VERSION 5.7 ;
  NOWIREEXTENSIONATPIN ON ;
  DIVIDERCHAR "/" ;
  BUSBITCHARS "[]" ;
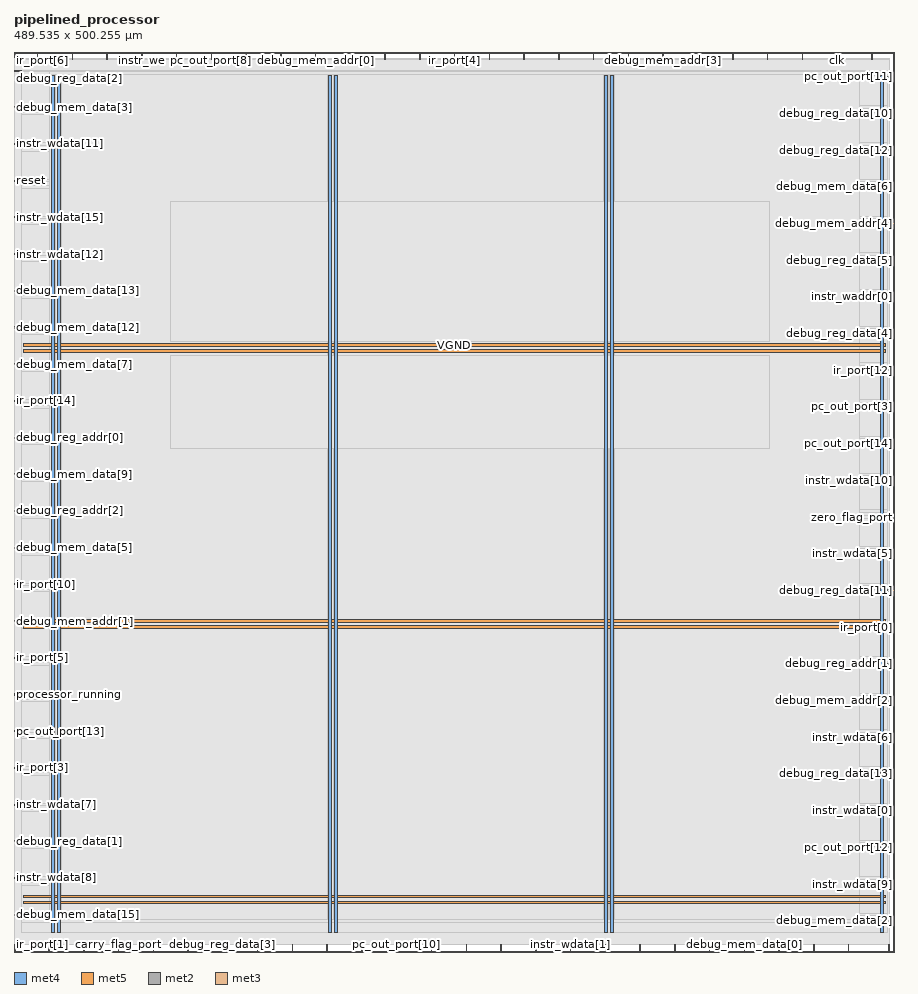
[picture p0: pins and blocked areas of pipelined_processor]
MACRO pipelined_processor
  CLASS BLOCK ;
  FOREIGN pipelined_processor ;
  ORIGIN 0.000 0.000 ;
  SIZE 489.535 BY 500.255 ;
  PIN VGND
    DIRECTION INOUT ;
    USE GROUND ;
    PORT
      LAYER met4 ;
        RECT 24.340 10.640 25.940 487.120 ;
    END
    PORT
      LAYER met4 ;
        RECT 177.940 10.640 179.540 487.120 ;
    END
    PORT
      LAYER met4 ;
        RECT 331.540 10.640 333.140 487.120 ;
    END
    PORT
      LAYER met5 ;
        RECT 5.280 30.030 484.160 31.630 ;
    END
    PORT
      LAYER met5 ;
        RECT 5.280 183.210 484.160 184.810 ;
    END
    PORT
      LAYER met5 ;
        RECT 5.280 336.390 484.160 337.990 ;
    END
  END VGND
  PIN VPWR
    DIRECTION INOUT ;
    USE POWER ;
    PORT
      LAYER met4 ;
        RECT 21.040 10.640 22.640 487.120 ;
    END
    PORT
      LAYER met4 ;
        RECT 174.640 10.640 176.240 487.120 ;
    END
    PORT
      LAYER met4 ;
        RECT 328.240 10.640 329.840 487.120 ;
    END
    PORT
      LAYER met4 ;
        RECT 481.840 10.640 483.440 487.120 ;
    END
    PORT
      LAYER met5 ;
        RECT 5.280 26.730 484.160 28.330 ;
    END
    PORT
      LAYER met5 ;
        RECT 5.280 179.910 484.160 181.510 ;
    END
    PORT
      LAYER met5 ;
        RECT 5.280 333.090 484.160 334.690 ;
    END
  END VPWR
  PIN carry_flag_port
    DIRECTION OUTPUT TRISTATE ;
    USE SIGNAL ;
    ANTENNADIFFAREA 0.795200 ;
    PORT
      LAYER met2 ;
        RECT 58.050 0.000 58.330 4.000 ;
    END
  END carry_flag_port
  PIN clk
    DIRECTION INPUT ;
    USE SIGNAL ;
    ANTENNAGATEAREA 1.721400 ;
    ANTENNADIFFAREA 0.869400 ;
    PORT
      LAYER met2 ;
        RECT 457.330 496.255 457.610 500.255 ;
    END
  END clk
  PIN debug_mem_addr[0]
    DIRECTION INPUT ;
    USE SIGNAL ;
    ANTENNAGATEAREA 0.196500 ;
    PORT
      LAYER met2 ;
        RECT 167.530 496.255 167.810 500.255 ;
    END
  END debug_mem_addr[0]
  PIN debug_mem_addr[1]
    DIRECTION INPUT ;
    USE SIGNAL ;
    ANTENNAGATEAREA 0.247500 ;
    PORT
      LAYER met3 ;
        RECT 0.000 183.640 4.000 184.240 ;
    END
  END debug_mem_addr[1]
  PIN debug_mem_addr[2]
    DIRECTION INPUT ;
    USE SIGNAL ;
    ANTENNAGATEAREA 0.213000 ;
    PORT
      LAYER met3 ;
        RECT 485.535 139.440 489.535 140.040 ;
    END
  END debug_mem_addr[2]
  PIN debug_mem_addr[3]
    DIRECTION INPUT ;
    USE SIGNAL ;
    ANTENNAGATEAREA 0.213000 ;
    PORT
      LAYER met2 ;
        RECT 360.730 496.255 361.010 500.255 ;
    END
  END debug_mem_addr[3]
  PIN debug_mem_addr[4]
    DIRECTION INPUT ;
    USE SIGNAL ;
    ANTENNAGATEAREA 0.213000 ;
    PORT
      LAYER met3 ;
        RECT 485.535 404.640 489.535 405.240 ;
    END
  END debug_mem_addr[4]
  PIN debug_mem_addr[5]
    DIRECTION INPUT ;
    USE SIGNAL ;
    ANTENNAGATEAREA 0.213000 ;
    PORT
      LAYER met2 ;
        RECT 322.090 496.255 322.370 500.255 ;
    END
  END debug_mem_addr[5]
  PIN debug_mem_data[0]
    DIRECTION OUTPUT TRISTATE ;
    USE SIGNAL ;
    ANTENNADIFFAREA 0.795200 ;
    PORT
      LAYER met2 ;
        RECT 405.810 0.000 406.090 4.000 ;
    END
  END debug_mem_data[0]
  PIN debug_mem_data[10]
    DIRECTION OUTPUT TRISTATE ;
    USE SIGNAL ;
    ANTENNADIFFAREA 0.795200 ;
    PORT
      LAYER met2 ;
        RECT 186.850 496.255 187.130 500.255 ;
    END
  END debug_mem_data[10]
  PIN debug_mem_data[11]
    DIRECTION OUTPUT TRISTATE ;
    USE SIGNAL ;
    ANTENNADIFFAREA 0.795200 ;
    PORT
      LAYER met2 ;
        RECT 425.130 0.000 425.410 4.000 ;
    END
  END debug_mem_data[11]
  PIN debug_mem_data[12]
    DIRECTION OUTPUT TRISTATE ;
    USE SIGNAL ;
    ANTENNADIFFAREA 0.795200 ;
    PORT
      LAYER met3 ;
        RECT 0.000 346.840 4.000 347.440 ;
    END
  END debug_mem_data[12]
  PIN debug_mem_data[13]
    DIRECTION OUTPUT TRISTATE ;
    USE SIGNAL ;
    ANTENNADIFFAREA 0.795200 ;
    PORT
      LAYER met3 ;
        RECT 0.000 367.240 4.000 367.840 ;
    END
  END debug_mem_data[13]
  PIN debug_mem_data[14]
    DIRECTION OUTPUT TRISTATE ;
    USE SIGNAL ;
    ANTENNADIFFAREA 0.795200 ;
    PORT
      LAYER met2 ;
        RECT 347.850 0.000 348.130 4.000 ;
    END
  END debug_mem_data[14]
  PIN debug_mem_data[15]
    DIRECTION OUTPUT TRISTATE ;
    USE SIGNAL ;
    ANTENNADIFFAREA 0.795200 ;
    PORT
      LAYER met3 ;
        RECT 0.000 20.440 4.000 21.040 ;
    END
  END debug_mem_data[15]
  PIN debug_mem_data[1]
    DIRECTION OUTPUT TRISTATE ;
    USE SIGNAL ;
    ANTENNADIFFAREA 0.795200 ;
    PORT
      LAYER met2 ;
        RECT 148.210 496.255 148.490 500.255 ;
    END
  END debug_mem_data[1]
  PIN debug_mem_data[2]
    DIRECTION OUTPUT TRISTATE ;
    USE SIGNAL ;
    ANTENNADIFFAREA 0.445500 ;
    PORT
      LAYER met3 ;
        RECT 485.535 17.040 489.535 17.640 ;
    END
  END debug_mem_data[2]
  PIN debug_mem_data[3]
    DIRECTION OUTPUT TRISTATE ;
    USE SIGNAL ;
    ANTENNADIFFAREA 0.795200 ;
    PORT
      LAYER met3 ;
        RECT 0.000 469.240 4.000 469.840 ;
    END
  END debug_mem_data[3]
  PIN debug_mem_data[4]
    DIRECTION OUTPUT TRISTATE ;
    USE SIGNAL ;
    ANTENNADIFFAREA 0.795200 ;
    PORT
      LAYER met2 ;
        RECT 463.770 0.000 464.050 4.000 ;
    END
  END debug_mem_data[4]
  PIN debug_mem_data[5]
    DIRECTION OUTPUT TRISTATE ;
    USE SIGNAL ;
    ANTENNADIFFAREA 0.795200 ;
    PORT
      LAYER met3 ;
        RECT 0.000 224.440 4.000 225.040 ;
    END
  END debug_mem_data[5]
  PIN debug_mem_data[6]
    DIRECTION OUTPUT TRISTATE ;
    USE SIGNAL ;
    ANTENNADIFFAREA 0.445500 ;
    PORT
      LAYER met3 ;
        RECT 485.535 425.040 489.535 425.640 ;
    END
  END debug_mem_data[6]
  PIN debug_mem_data[7]
    DIRECTION OUTPUT TRISTATE ;
    USE SIGNAL ;
    ANTENNADIFFAREA 0.795200 ;
    PORT
      LAYER met3 ;
        RECT 0.000 326.440 4.000 327.040 ;
    END
  END debug_mem_data[7]
  PIN debug_mem_data[8]
    DIRECTION OUTPUT TRISTATE ;
    USE SIGNAL ;
    ANTENNADIFFAREA 0.795200 ;
    PORT
      LAYER met2 ;
        RECT 51.610 496.255 51.890 500.255 ;
    END
  END debug_mem_data[8]
  PIN debug_mem_data[9]
    DIRECTION OUTPUT TRISTATE ;
    USE SIGNAL ;
    ANTENNADIFFAREA 0.795200 ;
    PORT
      LAYER met3 ;
        RECT 0.000 265.240 4.000 265.840 ;
    END
  END debug_mem_data[9]
  PIN debug_reg_addr[0]
    DIRECTION INPUT ;
    USE SIGNAL ;
    ANTENNAGATEAREA 0.247500 ;
    PORT
      LAYER met3 ;
        RECT 0.000 285.640 4.000 286.240 ;
    END
  END debug_reg_addr[0]
  PIN debug_reg_addr[1]
    DIRECTION INPUT ;
    USE SIGNAL ;
    ANTENNAGATEAREA 0.159000 ;
    PORT
      LAYER met3 ;
        RECT 485.535 159.840 489.535 160.440 ;
    END
  END debug_reg_addr[1]
  PIN debug_reg_addr[2]
    DIRECTION INPUT ;
    USE SIGNAL ;
    ANTENNAGATEAREA 0.247500 ;
    PORT
      LAYER met3 ;
        RECT 0.000 244.840 4.000 245.440 ;
    END
  END debug_reg_addr[2]
  PIN debug_reg_data[0]
    DIRECTION OUTPUT TRISTATE ;
    USE SIGNAL ;
    ANTENNADIFFAREA 0.795200 ;
    PORT
      LAYER met2 ;
        RECT 193.290 0.000 193.570 4.000 ;
    END
  END debug_reg_data[0]
  PIN debug_reg_data[10]
    DIRECTION OUTPUT TRISTATE ;
    USE SIGNAL ;
    ANTENNADIFFAREA 0.445500 ;
    PORT
      LAYER met3 ;
        RECT 485.535 465.840 489.535 466.440 ;
    END
  END debug_reg_data[10]
  PIN debug_reg_data[11]
    DIRECTION OUTPUT TRISTATE ;
    USE SIGNAL ;
    ANTENNADIFFAREA 0.795200 ;
    PORT
      LAYER met3 ;
        RECT 485.535 200.640 489.535 201.240 ;
    END
  END debug_reg_data[11]
  PIN debug_reg_data[12]
    DIRECTION OUTPUT TRISTATE ;
    USE SIGNAL ;
    ANTENNADIFFAREA 0.445500 ;
    PORT
      LAYER met3 ;
        RECT 485.535 445.440 489.535 446.040 ;
    END
  END debug_reg_data[12]
  PIN debug_reg_data[13]
    DIRECTION OUTPUT TRISTATE ;
    USE SIGNAL ;
    ANTENNADIFFAREA 0.445500 ;
    PORT
      LAYER met3 ;
        RECT 485.535 98.640 489.535 99.240 ;
    END
  END debug_reg_data[13]
  PIN debug_reg_data[14]
    DIRECTION OUTPUT TRISTATE ;
    USE SIGNAL ;
    ANTENNADIFFAREA 0.795200 ;
    PORT
      LAYER met2 ;
        RECT 302.770 496.255 303.050 500.255 ;
    END
  END debug_reg_data[14]
  PIN debug_reg_data[15]
    DIRECTION OUTPUT TRISTATE ;
    USE SIGNAL ;
    ANTENNADIFFAREA 0.795200 ;
    PORT
      LAYER met2 ;
        RECT 225.490 496.255 225.770 500.255 ;
    END
  END debug_reg_data[15]
  PIN debug_reg_data[1]
    DIRECTION OUTPUT TRISTATE ;
    USE SIGNAL ;
    ANTENNADIFFAREA 0.795200 ;
    PORT
      LAYER met3 ;
        RECT 0.000 61.240 4.000 61.840 ;
    END
  END debug_reg_data[1]
  PIN debug_reg_data[2]
    DIRECTION OUTPUT TRISTATE ;
    USE SIGNAL ;
    ANTENNADIFFAREA 0.795200 ;
    PORT
      LAYER met3 ;
        RECT 0.000 489.640 4.000 490.240 ;
    END
  END debug_reg_data[2]
  PIN debug_reg_data[3]
    DIRECTION OUTPUT TRISTATE ;
    USE SIGNAL ;
    ANTENNADIFFAREA 0.795200 ;
    PORT
      LAYER met2 ;
        RECT 116.010 0.000 116.290 4.000 ;
    END
  END debug_reg_data[3]
  PIN debug_reg_data[4]
    DIRECTION OUTPUT TRISTATE ;
    USE SIGNAL ;
    ANTENNADIFFAREA 0.795200 ;
    PORT
      LAYER met3 ;
        RECT 485.535 343.440 489.535 344.040 ;
    END
  END debug_reg_data[4]
  PIN debug_reg_data[5]
    DIRECTION OUTPUT TRISTATE ;
    USE SIGNAL ;
    ANTENNADIFFAREA 0.795200 ;
    PORT
      LAYER met3 ;
        RECT 485.535 384.240 489.535 384.840 ;
    END
  END debug_reg_data[5]
  PIN debug_reg_data[6]
    DIRECTION OUTPUT TRISTATE ;
    USE SIGNAL ;
    ANTENNADIFFAREA 0.795200 ;
    PORT
      LAYER met2 ;
        RECT 206.170 496.255 206.450 500.255 ;
    END
  END debug_reg_data[6]
  PIN debug_reg_data[7]
    DIRECTION OUTPUT TRISTATE ;
    USE SIGNAL ;
    ANTENNADIFFAREA 0.795200 ;
    PORT
      LAYER met2 ;
        RECT 264.130 496.255 264.410 500.255 ;
    END
  END debug_reg_data[7]
  PIN debug_reg_data[8]
    DIRECTION OUTPUT TRISTATE ;
    USE SIGNAL ;
    ANTENNADIFFAREA 0.795200 ;
    PORT
      LAYER met2 ;
        RECT 418.690 496.255 418.970 500.255 ;
    END
  END debug_reg_data[8]
  PIN debug_reg_data[9]
    DIRECTION OUTPUT TRISTATE ;
    USE SIGNAL ;
    ANTENNADIFFAREA 0.795200 ;
    PORT
      LAYER met2 ;
        RECT 486.310 0.000 486.590 4.000 ;
    END
  END debug_reg_data[9]
  PIN instr_waddr[0]
    DIRECTION INPUT ;
    USE SIGNAL ;
    ANTENNAGATEAREA 0.247500 ;
    PORT
      LAYER met3 ;
        RECT 485.535 363.840 489.535 364.440 ;
    END
  END instr_waddr[0]
  PIN instr_waddr[1]
    DIRECTION INPUT ;
    USE SIGNAL ;
    ANTENNAGATEAREA 0.426000 ;
    PORT
      LAYER met2 ;
        RECT 476.650 496.255 476.930 500.255 ;
    END
  END instr_waddr[1]
  PIN instr_waddr[2]
    DIRECTION INPUT ;
    USE SIGNAL ;
    ANTENNAGATEAREA 0.247500 ;
    PORT
      LAYER met2 ;
        RECT 283.450 496.255 283.730 500.255 ;
    END
  END instr_waddr[2]
  PIN instr_waddr[3]
    DIRECTION INPUT ;
    USE SIGNAL ;
    ANTENNAGATEAREA 0.213000 ;
    PORT
      LAYER met2 ;
        RECT 173.970 0.000 174.250 4.000 ;
    END
  END instr_waddr[3]
  PIN instr_wdata[0]
    DIRECTION INPUT ;
    USE SIGNAL ;
    ANTENNAGATEAREA 0.213000 ;
    PORT
      LAYER met3 ;
        RECT 485.535 78.240 489.535 78.840 ;
    END
  END instr_wdata[0]
  PIN instr_wdata[10]
    DIRECTION INPUT ;
    USE SIGNAL ;
    ANTENNAGATEAREA 0.213000 ;
    PORT
      LAYER met3 ;
        RECT 485.535 261.840 489.535 262.440 ;
    END
  END instr_wdata[10]
  PIN instr_wdata[11]
    DIRECTION INPUT ;
    USE SIGNAL ;
    ANTENNAGATEAREA 0.159000 ;
    PORT
      LAYER met3 ;
        RECT 0.000 448.840 4.000 449.440 ;
    END
  END instr_wdata[11]
  PIN instr_wdata[12]
    DIRECTION INPUT ;
    USE SIGNAL ;
    ANTENNAGATEAREA 0.213000 ;
    PORT
      LAYER met3 ;
        RECT 0.000 387.640 4.000 388.240 ;
    END
  END instr_wdata[12]
  PIN instr_wdata[13]
    DIRECTION INPUT ;
    USE SIGNAL ;
    ANTENNAGATEAREA 0.159000 ;
    PORT
      LAYER met2 ;
        RECT 128.890 496.255 129.170 500.255 ;
    END
  END instr_wdata[13]
  PIN instr_wdata[14]
    DIRECTION INPUT ;
    USE SIGNAL ;
    ANTENNAGATEAREA 0.213000 ;
    PORT
      LAYER met2 ;
        RECT 367.170 0.000 367.450 4.000 ;
    END
  END instr_wdata[14]
  PIN instr_wdata[15]
    DIRECTION INPUT ;
    USE SIGNAL ;
    ANTENNAGATEAREA 0.213000 ;
    PORT
      LAYER met3 ;
        RECT 0.000 408.040 4.000 408.640 ;
    END
  END instr_wdata[15]
  PIN instr_wdata[1]
    DIRECTION INPUT ;
    USE SIGNAL ;
    ANTENNAGATEAREA 0.159000 ;
    PORT
      LAYER met2 ;
        RECT 309.210 0.000 309.490 4.000 ;
    END
  END instr_wdata[1]
  PIN instr_wdata[2]
    DIRECTION INPUT ;
    USE SIGNAL ;
    ANTENNAGATEAREA 0.196500 ;
    PORT
      LAYER met2 ;
        RECT 38.730 0.000 39.010 4.000 ;
    END
  END instr_wdata[2]
  PIN instr_wdata[3]
    DIRECTION INPUT ;
    USE SIGNAL ;
    ANTENNAGATEAREA 0.196500 ;
    PORT
      LAYER met2 ;
        RECT 135.330 0.000 135.610 4.000 ;
    END
  END instr_wdata[3]
  PIN instr_wdata[4]
    DIRECTION INPUT ;
    USE SIGNAL ;
    ANTENNAGATEAREA 0.213000 ;
    PORT
      LAYER met2 ;
        RECT 444.450 0.000 444.730 4.000 ;
    END
  END instr_wdata[4]
  PIN instr_wdata[5]
    DIRECTION INPUT ;
    USE SIGNAL ;
    ANTENNAGATEAREA 0.247500 ;
    PORT
      LAYER met3 ;
        RECT 485.535 221.040 489.535 221.640 ;
    END
  END instr_wdata[5]
  PIN instr_wdata[6]
    DIRECTION INPUT ;
    USE SIGNAL ;
    ANTENNAGATEAREA 0.213000 ;
    PORT
      LAYER met3 ;
        RECT 485.535 119.040 489.535 119.640 ;
    END
  END instr_wdata[6]
  PIN instr_wdata[7]
    DIRECTION INPUT ;
    USE SIGNAL ;
    ANTENNAGATEAREA 0.196500 ;
    PORT
      LAYER met3 ;
        RECT 0.000 81.640 4.000 82.240 ;
    END
  END instr_wdata[7]
  PIN instr_wdata[8]
    DIRECTION INPUT ;
    USE SIGNAL ;
    ANTENNAGATEAREA 0.196500 ;
    PORT
      LAYER met3 ;
        RECT 0.000 40.840 4.000 41.440 ;
    END
  END instr_wdata[8]
  PIN instr_wdata[9]
    DIRECTION INPUT ;
    USE SIGNAL ;
    ANTENNAGATEAREA 0.213000 ;
    PORT
      LAYER met3 ;
        RECT 485.535 37.440 489.535 38.040 ;
    END
  END instr_wdata[9]
  PIN instr_we
    DIRECTION INPUT ;
    USE SIGNAL ;
    ANTENNAGATEAREA 0.742500 ;
    PORT
      LAYER met2 ;
        RECT 70.930 496.255 71.210 500.255 ;
    END
  END instr_we
  PIN ir_port[0]
    DIRECTION OUTPUT TRISTATE ;
    USE SIGNAL ;
    ANTENNADIFFAREA 0.795200 ;
    PORT
      LAYER met3 ;
        RECT 485.535 180.240 489.535 180.840 ;
    END
  END ir_port[0]
  PIN ir_port[10]
    DIRECTION OUTPUT TRISTATE ;
    USE SIGNAL ;
    ANTENNADIFFAREA 0.795200 ;
    PORT
      LAYER met3 ;
        RECT 0.000 204.040 4.000 204.640 ;
    END
  END ir_port[10]
  PIN ir_port[11]
    DIRECTION OUTPUT TRISTATE ;
    USE SIGNAL ;
    ANTENNADIFFAREA 0.795200 ;
    PORT
      LAYER met2 ;
        RECT 386.490 0.000 386.770 4.000 ;
    END
  END ir_port[11]
  PIN ir_port[12]
    DIRECTION OUTPUT TRISTATE ;
    USE SIGNAL ;
    ANTENNADIFFAREA 0.795200 ;
    PORT
      LAYER met3 ;
        RECT 485.535 323.040 489.535 323.640 ;
    END
  END ir_port[12]
  PIN ir_port[13]
    DIRECTION OUTPUT TRISTATE ;
    USE SIGNAL ;
    ANTENNADIFFAREA 0.795200 ;
    PORT
      LAYER met2 ;
        RECT 90.250 496.255 90.530 500.255 ;
    END
  END ir_port[13]
  PIN ir_port[14]
    DIRECTION OUTPUT TRISTATE ;
    USE SIGNAL ;
    ANTENNADIFFAREA 0.795200 ;
    PORT
      LAYER met3 ;
        RECT 0.000 306.040 4.000 306.640 ;
    END
  END ir_port[14]
  PIN ir_port[15]
    DIRECTION OUTPUT TRISTATE ;
    USE SIGNAL ;
    ANTENNADIFFAREA 0.795200 ;
    PORT
      LAYER met2 ;
        RECT 231.930 0.000 232.210 4.000 ;
    END
  END ir_port[15]
  PIN ir_port[1]
    DIRECTION OUTPUT TRISTATE ;
    USE SIGNAL ;
    ANTENNADIFFAREA 0.795200 ;
    PORT
      LAYER met2 ;
        RECT 0.090 0.000 0.370 4.000 ;
    END
  END ir_port[1]
  PIN ir_port[2]
    DIRECTION OUTPUT TRISTATE ;
    USE SIGNAL ;
    ANTENNADIFFAREA 0.795200 ;
    PORT
      LAYER met2 ;
        RECT 289.890 0.000 290.170 4.000 ;
    END
  END ir_port[2]
  PIN ir_port[3]
    DIRECTION OUTPUT TRISTATE ;
    USE SIGNAL ;
    ANTENNADIFFAREA 0.795200 ;
    PORT
      LAYER met3 ;
        RECT 0.000 102.040 4.000 102.640 ;
    END
  END ir_port[3]
  PIN ir_port[4]
    DIRECTION OUTPUT TRISTATE ;
    USE SIGNAL ;
    ANTENNADIFFAREA 0.795200 ;
    PORT
      LAYER met2 ;
        RECT 244.810 496.255 245.090 500.255 ;
    END
  END ir_port[4]
  PIN ir_port[5]
    DIRECTION OUTPUT TRISTATE ;
    USE SIGNAL ;
    ANTENNADIFFAREA 0.795200 ;
    PORT
      LAYER met3 ;
        RECT 0.000 163.240 4.000 163.840 ;
    END
  END ir_port[5]
  PIN ir_port[6]
    DIRECTION OUTPUT TRISTATE ;
    USE SIGNAL ;
    ANTENNADIFFAREA 0.795200 ;
    PORT
      LAYER met2 ;
        RECT 12.970 496.255 13.250 500.255 ;
    END
  END ir_port[6]
  PIN ir_port[7]
    DIRECTION OUTPUT TRISTATE ;
    USE SIGNAL ;
    ANTENNADIFFAREA 0.795200 ;
    PORT
      LAYER met2 ;
        RECT 77.370 0.000 77.650 4.000 ;
    END
  END ir_port[7]
  PIN ir_port[8]
    DIRECTION OUTPUT TRISTATE ;
    USE SIGNAL ;
    ANTENNADIFFAREA 0.795200 ;
    PORT
      LAYER met2 ;
        RECT 19.410 0.000 19.690 4.000 ;
    END
  END ir_port[8]
  PIN ir_port[9]
    DIRECTION OUTPUT TRISTATE ;
    USE SIGNAL ;
    ANTENNADIFFAREA 0.795200 ;
    PORT
      LAYER met2 ;
        RECT 438.010 496.255 438.290 500.255 ;
    END
  END ir_port[9]
  PIN pc_out_port[0]
    DIRECTION OUTPUT TRISTATE ;
    USE SIGNAL ;
    ANTENNADIFFAREA 0.795200 ;
    PORT
      LAYER met2 ;
        RECT 341.410 496.255 341.690 500.255 ;
    END
  END pc_out_port[0]
  PIN pc_out_port[10]
    DIRECTION OUTPUT TRISTATE ;
    USE SIGNAL ;
    ANTENNADIFFAREA 0.795200 ;
    PORT
      LAYER met2 ;
        RECT 212.610 0.000 212.890 4.000 ;
    END
  END pc_out_port[10]
  PIN pc_out_port[11]
    DIRECTION OUTPUT TRISTATE ;
    USE SIGNAL ;
    ANTENNADIFFAREA 0.795200 ;
    PORT
      LAYER met3 ;
        RECT 485.535 486.240 489.535 486.840 ;
    END
  END pc_out_port[11]
  PIN pc_out_port[12]
    DIRECTION OUTPUT TRISTATE ;
    USE SIGNAL ;
    ANTENNADIFFAREA 0.445500 ;
    PORT
      LAYER met3 ;
        RECT 485.535 57.840 489.535 58.440 ;
    END
  END pc_out_port[12]
  PIN pc_out_port[13]
    DIRECTION OUTPUT TRISTATE ;
    USE SIGNAL ;
    ANTENNADIFFAREA 0.795200 ;
    PORT
      LAYER met3 ;
        RECT 0.000 122.440 4.000 123.040 ;
    END
  END pc_out_port[13]
  PIN pc_out_port[14]
    DIRECTION OUTPUT TRISTATE ;
    USE SIGNAL ;
    ANTENNADIFFAREA 0.795200 ;
    PORT
      LAYER met3 ;
        RECT 485.535 282.240 489.535 282.840 ;
    END
  END pc_out_port[14]
  PIN pc_out_port[15]
    DIRECTION OUTPUT TRISTATE ;
    USE SIGNAL ;
    ANTENNADIFFAREA 0.795200 ;
    PORT
      LAYER met2 ;
        RECT 96.690 0.000 96.970 4.000 ;
    END
  END pc_out_port[15]
  PIN pc_out_port[1]
    DIRECTION OUTPUT TRISTATE ;
    USE SIGNAL ;
    ANTENNADIFFAREA 0.795200 ;
    PORT
      LAYER met2 ;
        RECT 154.650 0.000 154.930 4.000 ;
    END
  END pc_out_port[1]
  PIN pc_out_port[2]
    DIRECTION OUTPUT TRISTATE ;
    USE SIGNAL ;
    ANTENNADIFFAREA 0.795200 ;
    PORT
      LAYER met2 ;
        RECT 251.250 0.000 251.530 4.000 ;
    END
  END pc_out_port[2]
  PIN pc_out_port[3]
    DIRECTION OUTPUT TRISTATE ;
    USE SIGNAL ;
    ANTENNADIFFAREA 0.795200 ;
    PORT
      LAYER met3 ;
        RECT 485.535 302.640 489.535 303.240 ;
    END
  END pc_out_port[3]
  PIN pc_out_port[4]
    DIRECTION OUTPUT TRISTATE ;
    USE SIGNAL ;
    ANTENNADIFFAREA 0.795200 ;
    PORT
      LAYER met2 ;
        RECT 270.570 0.000 270.850 4.000 ;
    END
  END pc_out_port[4]
  PIN pc_out_port[5]
    DIRECTION OUTPUT TRISTATE ;
    USE SIGNAL ;
    ANTENNADIFFAREA 0.795200 ;
    PORT
      LAYER met2 ;
        RECT 399.370 496.255 399.650 500.255 ;
    END
  END pc_out_port[5]
  PIN pc_out_port[6]
    DIRECTION OUTPUT TRISTATE ;
    USE SIGNAL ;
    ANTENNADIFFAREA 0.795200 ;
    PORT
      LAYER met2 ;
        RECT 380.050 496.255 380.330 500.255 ;
    END
  END pc_out_port[6]
  PIN pc_out_port[7]
    DIRECTION OUTPUT TRISTATE ;
    USE SIGNAL ;
    ANTENNADIFFAREA 0.795200 ;
    PORT
      LAYER met2 ;
        RECT 32.290 496.255 32.570 500.255 ;
    END
  END pc_out_port[7]
  PIN pc_out_port[8]
    DIRECTION OUTPUT TRISTATE ;
    USE SIGNAL ;
    ANTENNADIFFAREA 0.795200 ;
    PORT
      LAYER met2 ;
        RECT 109.570 496.255 109.850 500.255 ;
    END
  END pc_out_port[8]
  PIN pc_out_port[9]
    DIRECTION OUTPUT TRISTATE ;
    USE SIGNAL ;
    ANTENNADIFFAREA 0.795200 ;
    PORT
      LAYER met2 ;
        RECT 328.530 0.000 328.810 4.000 ;
    END
  END pc_out_port[9]
  PIN processor_running
    DIRECTION OUTPUT TRISTATE ;
    USE SIGNAL ;
    ANTENNADIFFAREA 0.795200 ;
    PORT
      LAYER met3 ;
        RECT 0.000 142.840 4.000 143.440 ;
    END
  END processor_running
  PIN reset
    DIRECTION INPUT ;
    USE SIGNAL ;
    ANTENNAGATEAREA 0.213000 ;
    PORT
      LAYER met3 ;
        RECT 0.000 428.440 4.000 429.040 ;
    END
  END reset
  PIN zero_flag_port
    DIRECTION OUTPUT TRISTATE ;
    USE SIGNAL ;
    ANTENNADIFFAREA 0.795200 ;
    PORT
      LAYER met3 ;
        RECT 485.535 241.440 489.535 242.040 ;
    END
  END zero_flag_port
  OBS
      LAYER li1 ;
        RECT 5.520 10.795 483.920 486.965 ;
      LAYER met1 ;
        RECT 0.070 8.200 486.610 487.520 ;
      LAYER met2 ;
        RECT 0.100 495.975 12.690 496.810 ;
        RECT 13.530 495.975 32.010 496.810 ;
        RECT 32.850 495.975 51.330 496.810 ;
        RECT 52.170 495.975 70.650 496.810 ;
        RECT 71.490 495.975 89.970 496.810 ;
        RECT 90.810 495.975 109.290 496.810 ;
        RECT 110.130 495.975 128.610 496.810 ;
        RECT 129.450 495.975 147.930 496.810 ;
        RECT 148.770 495.975 167.250 496.810 ;
        RECT 168.090 495.975 186.570 496.810 ;
        RECT 187.410 495.975 205.890 496.810 ;
        RECT 206.730 495.975 225.210 496.810 ;
        RECT 226.050 495.975 244.530 496.810 ;
        RECT 245.370 495.975 263.850 496.810 ;
        RECT 264.690 495.975 283.170 496.810 ;
        RECT 284.010 495.975 302.490 496.810 ;
        RECT 303.330 495.975 321.810 496.810 ;
        RECT 322.650 495.975 341.130 496.810 ;
        RECT 341.970 495.975 360.450 496.810 ;
        RECT 361.290 495.975 379.770 496.810 ;
        RECT 380.610 495.975 399.090 496.810 ;
        RECT 399.930 495.975 418.410 496.810 ;
        RECT 419.250 495.975 437.730 496.810 ;
        RECT 438.570 495.975 457.050 496.810 ;
        RECT 457.890 495.975 476.370 496.810 ;
        RECT 477.210 495.975 486.580 496.810 ;
        RECT 0.100 4.280 486.580 495.975 ;
        RECT 0.650 4.000 19.130 4.280 ;
        RECT 19.970 4.000 38.450 4.280 ;
        RECT 39.290 4.000 57.770 4.280 ;
        RECT 58.610 4.000 77.090 4.280 ;
        RECT 77.930 4.000 96.410 4.280 ;
        RECT 97.250 4.000 115.730 4.280 ;
        RECT 116.570 4.000 135.050 4.280 ;
        RECT 135.890 4.000 154.370 4.280 ;
        RECT 155.210 4.000 173.690 4.280 ;
        RECT 174.530 4.000 193.010 4.280 ;
        RECT 193.850 4.000 212.330 4.280 ;
        RECT 213.170 4.000 231.650 4.280 ;
        RECT 232.490 4.000 250.970 4.280 ;
        RECT 251.810 4.000 270.290 4.280 ;
        RECT 271.130 4.000 289.610 4.280 ;
        RECT 290.450 4.000 308.930 4.280 ;
        RECT 309.770 4.000 328.250 4.280 ;
        RECT 329.090 4.000 347.570 4.280 ;
        RECT 348.410 4.000 366.890 4.280 ;
        RECT 367.730 4.000 386.210 4.280 ;
        RECT 387.050 4.000 405.530 4.280 ;
        RECT 406.370 4.000 424.850 4.280 ;
        RECT 425.690 4.000 444.170 4.280 ;
        RECT 445.010 4.000 463.490 4.280 ;
        RECT 464.330 4.000 486.030 4.280 ;
      LAYER met3 ;
        RECT 4.400 489.240 485.695 490.105 ;
        RECT 3.990 487.240 485.695 489.240 ;
        RECT 3.990 485.840 485.135 487.240 ;
        RECT 3.990 470.240 485.695 485.840 ;
        RECT 4.400 468.840 485.695 470.240 ;
        RECT 3.990 466.840 485.695 468.840 ;
        RECT 3.990 465.440 485.135 466.840 ;
        RECT 3.990 449.840 485.695 465.440 ;
        RECT 4.400 448.440 485.695 449.840 ;
        RECT 3.990 446.440 485.695 448.440 ;
        RECT 3.990 445.040 485.135 446.440 ;
        RECT 3.990 429.440 485.695 445.040 ;
        RECT 4.400 428.040 485.695 429.440 ;
        RECT 3.990 426.040 485.695 428.040 ;
        RECT 3.990 424.640 485.135 426.040 ;
        RECT 3.990 409.040 485.695 424.640 ;
        RECT 4.400 407.640 485.695 409.040 ;
        RECT 3.990 405.640 485.695 407.640 ;
        RECT 3.990 404.240 485.135 405.640 ;
        RECT 3.990 388.640 485.695 404.240 ;
        RECT 4.400 387.240 485.695 388.640 ;
        RECT 3.990 385.240 485.695 387.240 ;
        RECT 3.990 383.840 485.135 385.240 ;
        RECT 3.990 368.240 485.695 383.840 ;
        RECT 4.400 366.840 485.695 368.240 ;
        RECT 3.990 364.840 485.695 366.840 ;
        RECT 3.990 363.440 485.135 364.840 ;
        RECT 3.990 347.840 485.695 363.440 ;
        RECT 4.400 346.440 485.695 347.840 ;
        RECT 3.990 344.440 485.695 346.440 ;
        RECT 3.990 343.040 485.135 344.440 ;
        RECT 3.990 327.440 485.695 343.040 ;
        RECT 4.400 326.040 485.695 327.440 ;
        RECT 3.990 324.040 485.695 326.040 ;
        RECT 3.990 322.640 485.135 324.040 ;
        RECT 3.990 307.040 485.695 322.640 ;
        RECT 4.400 305.640 485.695 307.040 ;
        RECT 3.990 303.640 485.695 305.640 ;
        RECT 3.990 302.240 485.135 303.640 ;
        RECT 3.990 286.640 485.695 302.240 ;
        RECT 4.400 285.240 485.695 286.640 ;
        RECT 3.990 283.240 485.695 285.240 ;
        RECT 3.990 281.840 485.135 283.240 ;
        RECT 3.990 266.240 485.695 281.840 ;
        RECT 4.400 264.840 485.695 266.240 ;
        RECT 3.990 262.840 485.695 264.840 ;
        RECT 3.990 261.440 485.135 262.840 ;
        RECT 3.990 245.840 485.695 261.440 ;
        RECT 4.400 244.440 485.695 245.840 ;
        RECT 3.990 242.440 485.695 244.440 ;
        RECT 3.990 241.040 485.135 242.440 ;
        RECT 3.990 225.440 485.695 241.040 ;
        RECT 4.400 224.040 485.695 225.440 ;
        RECT 3.990 222.040 485.695 224.040 ;
        RECT 3.990 220.640 485.135 222.040 ;
        RECT 3.990 205.040 485.695 220.640 ;
        RECT 4.400 203.640 485.695 205.040 ;
        RECT 3.990 201.640 485.695 203.640 ;
        RECT 3.990 200.240 485.135 201.640 ;
        RECT 3.990 184.640 485.695 200.240 ;
        RECT 4.400 183.240 485.695 184.640 ;
        RECT 3.990 181.240 485.695 183.240 ;
        RECT 3.990 179.840 485.135 181.240 ;
        RECT 3.990 164.240 485.695 179.840 ;
        RECT 4.400 162.840 485.695 164.240 ;
        RECT 3.990 160.840 485.695 162.840 ;
        RECT 3.990 159.440 485.135 160.840 ;
        RECT 3.990 143.840 485.695 159.440 ;
        RECT 4.400 142.440 485.695 143.840 ;
        RECT 3.990 140.440 485.695 142.440 ;
        RECT 3.990 139.040 485.135 140.440 ;
        RECT 3.990 123.440 485.695 139.040 ;
        RECT 4.400 122.040 485.695 123.440 ;
        RECT 3.990 120.040 485.695 122.040 ;
        RECT 3.990 118.640 485.135 120.040 ;
        RECT 3.990 103.040 485.695 118.640 ;
        RECT 4.400 101.640 485.695 103.040 ;
        RECT 3.990 99.640 485.695 101.640 ;
        RECT 3.990 98.240 485.135 99.640 ;
        RECT 3.990 82.640 485.695 98.240 ;
        RECT 4.400 81.240 485.695 82.640 ;
        RECT 3.990 79.240 485.695 81.240 ;
        RECT 3.990 77.840 485.135 79.240 ;
        RECT 3.990 62.240 485.695 77.840 ;
        RECT 4.400 60.840 485.695 62.240 ;
        RECT 3.990 58.840 485.695 60.840 ;
        RECT 3.990 57.440 485.135 58.840 ;
        RECT 3.990 41.840 485.695 57.440 ;
        RECT 4.400 40.440 485.695 41.840 ;
        RECT 3.990 38.440 485.695 40.440 ;
        RECT 3.990 37.040 485.135 38.440 ;
        RECT 3.990 21.440 485.695 37.040 ;
        RECT 4.400 20.040 485.695 21.440 ;
        RECT 3.990 18.040 485.695 20.040 ;
        RECT 3.990 16.640 485.135 18.040 ;
        RECT 3.990 10.715 485.695 16.640 ;
      LAYER met4 ;
        RECT 19.615 487.520 469.825 489.425 ;
        RECT 19.615 17.855 20.640 487.520 ;
        RECT 23.040 17.855 23.940 487.520 ;
        RECT 26.340 17.855 174.240 487.520 ;
        RECT 176.640 17.855 177.540 487.520 ;
        RECT 179.940 17.855 327.840 487.520 ;
        RECT 330.240 17.855 331.140 487.520 ;
        RECT 333.540 17.855 469.825 487.520 ;
      LAYER met5 ;
        RECT 87.060 339.590 419.860 417.300 ;
        RECT 87.060 279.700 419.860 331.490 ;
  END
END pipelined_processor
END LIBRARY

